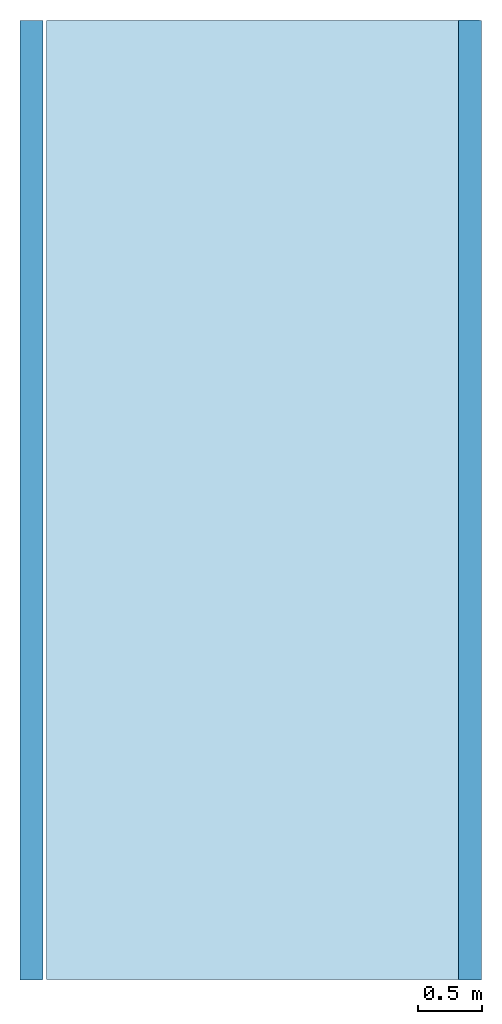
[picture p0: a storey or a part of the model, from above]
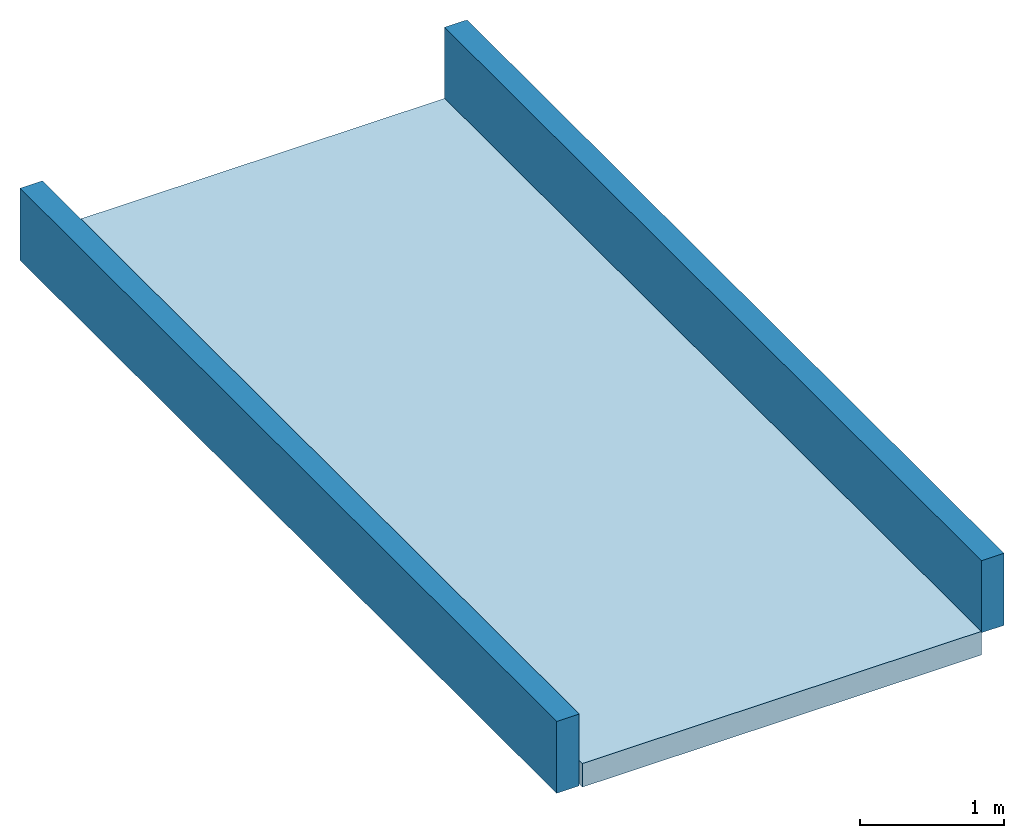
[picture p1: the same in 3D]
Properties of the parts of a building model (IFC2X3)

# File
Description: ViewDefinition [CoordinationView_V2.0]
Time: 2019-03-18T11:56:17
Written by: The EXPRESS Data Manager Version 5.02.0100.07 : 28 Aug 2013
Made in: 20170223_1515(x64) - Exporter 18.0.0.420 - Alternate UI 18.0.0.420
Comment: STEP Physical File produced by: The EXPRESS Data Manager Version 5.02.0100.07 : 28 Aug 2013 * Module: EDMstepFileFactory/EDMstandAlone * Creation date: Mon Mar 18 11:56:17 2019 * Host: A008-2016-12 * Database: C:\Users\D-DEVE~1\AppData\Local\Temp\{F924E7BE-AED8-4C60-A0E6-F540F420C843}\ifc * Database version: 5507 * Database creation date: Mon Mar 18 11:56:11 2019 * Schema: IFC2X3 * Model: DataRepository.ifc * Model creation date: Mon Mar 18 11:56:12 2019 * Header model: DataRepository.ifc_HeaderModel * Header model creation date: Mon Mar 18 11:56:12 2019 * EDMuser: sdai-user * EDMgroup: sdai-group * License ID and type: 5605 : Permanent license. Expiry date: * EDMstepFileFactory options: 020000

# IfcSite, Default
RefLatitude: 48, 51, 23, 999633; RefLongitude: 2, 21, 3, 553905; RefElevation: 0 m

# IfcBuilding
Pset_BuildingCommon - NumberOfStoreys: 3

# IfcBuildingStorey (3)
Name | LongName | Elevation (m)
Niveau 0 | Niveau 0 | -1.94916e-14
Niveau 1 | Niveau 1 | 3.3
Niveau 6 | Niveau 6 | 6.63

# IfcBeam: Poutre rectangulaire - Béton:180 x 250 mm (3)
In: Niveau 0
Type - PredefinedType: BEAM
Material: Béton - Béton coulé sur place
Pset_BeamCommon - LoadBearing: yes; IsExternal: no; Reference: 180 x 250 mm
Name (Poutre rectangulaire - Béton:180 x 250 mm:...) | Span (m) | Slope (deg)
237802 | 11.1 | 0
237840 | 9.745 | 2.05694
238378 | 3.3 | 0

# IfcBeam: Poutre rectangulaire - Béton:180 x 610 (2)
In: Niveau 6
Type - PredefinedType: BEAM
Material: Béton - Béton coulé sur place
Pset_BeamCommon - LoadBearing: yes; IsExternal: no; Slope: 0 deg; Reference: 180 x 610; Span: 7.42 m
Name (Poutre rectangulaire - Béton:180 x 610:...)
244297
244416

# IfcDoor: 0.93 x 2.04, PVC Panneau Plein:0.93 x 2.04:215848
In: Niveau 0
Type - OperationType: SINGLE_SWING_LEFT; ParameterTakesPrecedence: no; Sizeable: no; Material: PVC - Blanc
Type - PVC Panneau Plein:0.93 x 2.04:215848 - PanelOperation: SWINGING
OverallHeight: 2.09 m; OverallWidth: 1.03 m
Pset_DoorCommon - Reference: 0.93 x 2.04; IsExternal: no; ThermalTransmittance: 5.5617 kg/K/s3

# IfcDoor: 0.93 x 2.04, PVC Panneau Plein:0.93 x 2.04:225900
In: Niveau 0
Type - OperationType: SINGLE_SWING_LEFT; ParameterTakesPrecedence: no; Sizeable: no; Material: PVC - Blanc
Type - PVC Panneau Plein:0.93 x 2.04:225900 - PanelOperation: SWINGING
OverallHeight: 2.09 m; OverallWidth: 1.03 m
Pset_DoorCommon - Reference: 0.93 x 2.04; IsExternal: no; ThermalTransmittance: 5.5617 kg/K/s3

# IfcDoor: 0.93 x 2.04 (2)
In: Niveau 0
Type - OperationType: SINGLE_SWING_LEFT; ParameterTakesPrecedence: no; Sizeable: no; Material: PVC - Blanc
Type - PVC Panneau Plein:0.93 x 2.04:229988 - PanelOperation: SWINGING
OverallHeight: 2.09 m; OverallWidth: 1.03 m
Pset_DoorCommon - Reference: 0.93 x 2.04; IsExternal: no; ThermalTransmittance: 5.5617 kg/K/s3
Name (PVC Panneau Plein:0.93 x 2.04:...)
229988
233565

# IfcDoor: 0.93 x 2.04, PVC Panneau Plein:0.93 x 2.04:215253
In: Niveau 0
Type - OperationType: SINGLE_SWING_RIGHT; ParameterTakesPrecedence: no; Sizeable: no; Material: PVC - Blanc
Type - PVC Panneau Plein:0.93 x 2.04:215253 - PanelOperation: SWINGING
OverallHeight: 2.09 m; OverallWidth: 1.03 m
Pset_DoorCommon - Reference: 0.93 x 2.04; IsExternal: no; ThermalTransmittance: 5.5617 kg/K/s3

# IfcDoor: 0.93 x 2.04 (2)
In: Niveau 0
Type - OperationType: SINGLE_SWING_RIGHT; ParameterTakesPrecedence: no; Sizeable: no; Material: PVC - Blanc
Type - PVC Panneau Plein:0.93 x 2.04:225744 - PanelOperation: SWINGING
OverallHeight: 2.09 m; OverallWidth: 1.03 m
Pset_DoorCommon - Reference: 0.93 x 2.04; IsExternal: no; ThermalTransmittance: 5.5617 kg/K/s3
Name (PVC Panneau Plein:0.93 x 2.04:...)
225744
225848

# IfcDoor: 0.93 x 2.04, PVC Panneau Plein:0.93 x 2.04:229795
In: Niveau 0
Type - OperationType: SINGLE_SWING_RIGHT; ParameterTakesPrecedence: no; Sizeable: no; Material: PVC - Blanc
Type - PVC Panneau Plein:0.93 x 2.04:229795 - PanelOperation: SWINGING
OverallHeight: 2.09 m; OverallWidth: 1.03 m
Pset_DoorCommon - Reference: 0.93 x 2.04; IsExternal: no; ThermalTransmittance: 5.5617 kg/K/s3

# IfcDoor: Garage sectionnelle (2)
In: Niveau 0
Type - OperationType: ROLLINGUP; ParameterTakesPrecedence: no; Sizeable: no; Material: Plastique - Noir, Peinture - Grise, Verre
Type - Garage sectionnelle:Garage sectionnelle:225384 - PanelOperation: ROLLINGUP
OverallHeight: 2.56 m; OverallWidth: 4.12 m
Pset_DoorCommon - IsExternal: yes; Reference: Garage sectionnelle; ThermalTransmittance: 3.7021 kg/K/s3
Name (Garage sectionnelle:Garage sectionnelle:...)
225384
225567

# IfcDoor: Vitrée - 1.80 m x 2.15 m (2)
In: Niveau 1
Type - OperationType: DOUBLE_DOOR_SINGLE_SWING; ParameterTakesPrecedence: no; Sizeable: no; Material: PVC - Jaune, Verre, PVC - Gris foncé
Type - Ext. Double:Vitrée - 1.80 m x 2.15 m:315028 - PanelOperation: SWINGING
OverallHeight: 2.2 m; OverallWidth: 1.9 m
Pset_DoorCommon - IsExternal: yes; Reference: Vitrée - 1.80 m x 2.15 m; ThermalTransmittance: 3.6886 kg/K/s3
Name (Ext. Double:Vitrée - 1.80 m x 2.15 m:...)
315028
315358

# IfcDoor: Vitrée - 1.80 m x 2.15 m, Ext. Double:Vitrée - 1.80 m x 2.15 m:315140
In: Niveau 1
Type - OperationType: DOUBLE_DOOR_SINGLE_SWING; ParameterTakesPrecedence: no; Sizeable: no; Material: PVC - Jaune, Verre, PVC - Gris foncé
Type - Ext. Double:Vitrée - 1.80 m x 2.15 m:315140 - PanelOperation: SWINGING
OverallHeight: 2.2 m; OverallWidth: 1.9 m
Pset_DoorCommon - IsExternal: yes; Reference: Vitrée - 1.80 m x 2.15 m; ThermalTransmittance: 3.6886 kg/K/s3

# IfcSlab: Radier:Béton - 200mm (5)
In: Niveau 0
PredefinedType: BASESLAB; Material: Maçonnerie - Béton 0.2 m
Pset_SlabCommon - LoadBearing: yes; IsExternal: no; Reference: Béton - 200mm; PitchAngle: 0 deg
Name (Radier:Béton - 200mm:...)
227879
228000
228036
228069
233728

# IfcSlab: Sol:Dalle en béton - 200 (2)
PredefinedType: FLOOR; Material: Maçonnerie - Béton 0.2 m
Pset_SlabCommon - LoadBearing: yes; IsExternal: no; PitchAngle: 0 deg; Reference: Dalle en béton - 200
Name (Sol:Dalle en béton - 200:...) | In
240961 | Niveau 1
254807 | Niveau 6

# IfcWall: Mur de base:Ext. Voile BA 18 (2)
In: Niveau 0
Pset_WallCommon - LoadBearing: yes; ExtendToStructure: yes; IsExternal: yes; Reference: Ext. Voile BA 18
Name (Mur de base:Ext. Voile BA 18:...)
206892 | Material: Maçonnerie - Voile BA
207633

# IfcWallStandardCase: Mur de base:Ext. Voile BA 18 (18)
In: Niveau 0
Material: Maçonnerie - Voile BA 0.18 m
Pset_WallCommon - LoadBearing: yes; IsExternal: yes; Reference: Ext. Voile BA 18
Name (Mur de base:Ext. Voile BA 18:...) | ExtendToStructure
207049 | no
207252 | no
207928 | yes
208552 | yes
208999 | yes
209175 | yes
230415 | no
230882 | yes
230994 | no
231115 | no
231270 | no
231434 | no
231622 | no
231754 | no
234639 | no
234764 | no
234960 | no
236817 | no

# IfcWallStandardCase: Mur de base:Ext. Voile BA 18 + Isolant 12 (11)
Type - PredefinedType: STANDARD; Material: Maçonnerie - Voile BA 0.18 m, Maçonnerie - Isolant 0.12 m
Pset_WallCommon - Reference: Ext. Voile BA 18 + Isolant 12; LoadBearing: yes; IsExternal: yes
Name (Mur de base:Ext. Voile BA 18 + Isolant 12:...) | In | ExtendToStructure
205236 | Niveau 0 | yes
205963 | Niveau 0 | yes
206548 | Niveau 0 | yes
243467 | Niveau 1 | no
243960 | Niveau 1 | no
248220 | Niveau 1 | yes
248440 | Niveau 1 | yes
248773 | Niveau 1 | yes
249240 | Niveau 1 | yes
250600 | Niveau 1 | no
254541 | Niveau 1 | no

# IfcWallStandardCase: Mur de base:Refend. Voile BA 16 (4)
In: Niveau 0
Type - PredefinedType: STANDARD; Material: Maçonnerie - Voile BA 0.16 m
Pset_WallCommon - LoadBearing: yes; ExtendToStructure: yes; IsExternal: yes; Reference: Refend. Voile BA 16
Name (Mur de base:Refend. Voile BA 16:...)
209831
210158
210391
210516

# IfcWindow: 150x50 (6)
In: Niveau 0
Type - ParameterTakesPrecedence: no; Sizeable: no; Material: PVC Blanc, Verre
OverallHeight: 0.58 m; OverallWidth: 1.56 m
Pset_WindowCommon - IsExternal: yes; Reference: 150x50
Name (Rect 1 fixe:150x50:...)
219186
219318
219394
219467
219525
219602

# IfcWindow: 2.40m x 1.45m - Appui Béton (12)
In: Niveau 1
Type - OperationType: TRIPLE_PANEL_VERTICAL; ParameterTakesPrecedence: no; Sizeable: no; Material: Fenêtre - Poignée, Fenêtre - Appui, Fenêtre - Cadre, Fenêtre - Vitrage
OverallHeight: 1.58 m; OverallWidth: 2.5 m
Pset_WindowCommon - IsExternal: yes; Reference: 2.40m x 1.45m - Appui Béton
Name (3 Vantaux - Droits:2.40m x 1.45m - Appui Béton:...)
297654
297780
297845
297906
298094
298179
298311
298382
299029
299177
299281
299342

# IfcWindow: 50x50 (4)
In: Niveau 0
Type - ParameterTakesPrecedence: no; Sizeable: no; Material: PVC Blanc, Verre
OverallHeight: 0.58 m; OverallWidth: 0.56 m
Pset_WindowCommon - IsExternal: yes; Reference: 50x50
Name (Rect 1 fixe:50x50:...)
218300
218469
218538
218599

# IfcWindow: 50x50 ss doublage (2)
In: Niveau 0
Type - ParameterTakesPrecedence: no; Sizeable: no; Material: PVC Blanc, Verre
OverallHeight: 0.58 m; OverallWidth: 0.56 m
Pset_WindowCommon - IsExternal: yes; Reference: 50x50 ss doublage
Name (Rect 1 fixe:50x50 ss doublage:...)
218842
219029
